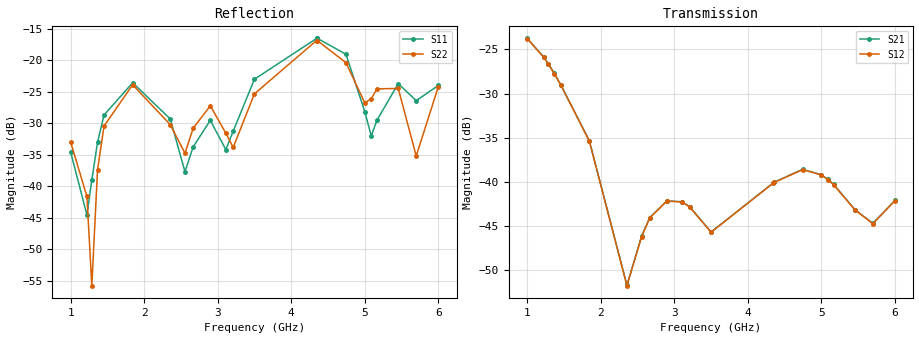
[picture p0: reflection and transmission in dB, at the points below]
!Agilent Technologies,E8364B,MY43040528,A.07.50.67
!Agilent E8364B: A.07.50.67
!Date: Sunday, March 01, 2026 22:28:23
!Correction: S11(Full 2 Port(1,2))
!S21(Full 2 Port(1,2))
!S12(Full 2 Port(1,2))
!S22(Full 2 Port(1,2))
!S2P File: Measurements: S11, S21, S12, S22:
# Hz S  dB  R 50
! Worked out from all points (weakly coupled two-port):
!   451 points, 1 GHz to 6 GHz, reference 50 ohm
!   highest |S21| = -23.76 dB at 1 GHz (marker M1); lowest = -51.7 dB at 2.356 GHz (marker M2)
!   lowest |S11| = -44.5 dB at 1.222 GHz (marker M3), VSWR 1.01, Z = 50.3 - j0.528 ohm
!   |S11| at or under -10 dB: start of sweep to end of sweep
!   |S22| runs from -55.8 to -16.8 dB; largest |S21 - S12| = 0.00026
!   S11 on the Smith chart (normalised r, x): 1 GHz: 1.04, +0.01; 4.356 GHz: 1.20, -0.26; 6 GHz: 0.96, -0.12
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1e9  -34.52 12.5  -23.76 154.9  -23.79 155.0  -32.95 -13.2
1.222222e9  -44.52 -62.1  -25.86 28.3  -25.89 28.3  -41.60 -32.7
1.288889e9  -38.99 -125.3  -26.66 -9.4  -26.69 -9.3  -55.75 -131.8
1.366667e9  -32.98 -157.7  -27.70 -52.8  -27.74 -52.7  -37.38 121.8
1.455556e9  -28.66 172.0  -29.00 -101.4  -29.02 -101.4  -30.41 93.3
1.844444e9  -23.56 83.1  -35.35 51.2  -35.38 51.2  -23.88 -8.5
2.355556e9  -29.30 13.3  -51.69 -148.9  -51.73 -148.9  -30.21 -93.9
2.555556e9  -37.69 32.4  -46.12 157.2  -46.17 157.2  -34.74 -72.5
2.666667e9  -33.74 67.6  -44.02 103.9  -44.06 104.1  -30.78 -64.0
2.9e9  -29.52 42.3  -42.13 -16.2  -42.16 -16.2  -27.22 -109.0
3.111111e9  -34.17 49.5  -42.24 -126.7  -42.28 -126.6  -31.55 -142.3
3.211111e9  -31.24 74.7  -42.83 -178.0  -42.86 -177.9  -33.82 -124.1
3.5e9  -23.00 49.7  -45.66 46.9  -45.69 46.9  -25.32 -130.4
4.344444e9  -16.54 -44.2  -40.11 23.4  -40.13 23.4  -16.86 111.3
4.355556e9  -16.52 -45.9  -40.03 17.4  -40.06 17.5  -16.88 109.0
4.744444e9  -19.04 -110.3  -38.57 161.5  -38.61 161.5  -20.37 36.6
5e9  -28.13 -137.6  -39.18 12.5  -39.21 12.5  -26.74 28.7
5.088889e9  -32.00 -107.9  -39.70 -40.5  -39.73 -40.6  -26.09 37.6
5.166667e9  -29.49 -78.0  -40.28 -87.5  -40.31 -87.5  -24.53 34.3
5.455556e9  -23.70 -104.6  -43.13 88.1  -43.16 88.2  -24.46 -20.7
5.7e9  -26.40 -114.2  -44.68 -88.0  -44.72 -88.0  -35.18 -13.5
6e9  -23.99 -104.9  -42.08 59.7  -42.12 59.6  -24.21 -4.1
